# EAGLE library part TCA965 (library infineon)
Window Discriminator Source: http://www.infineon.com/upload/Document/cmc_upload/documents/012/1090/tca965b_green_050217.pdf

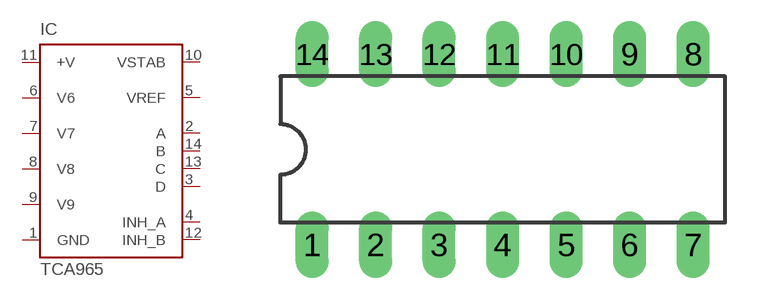
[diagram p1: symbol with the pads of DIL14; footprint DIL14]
Designator prefix IC

## TCA965 (OC_FARNELL: unknown; OC_NEWARK: unknown)  [DIL14]
1  GND  out
2  A  oc
3  D  oc
4  INH_A  in
5  VREF  pas
6  V6  in
7  V7  in
8  V8  in
9  V9  in
10  VSTAB  out
11  +V  out
12  INH_B  in
13  C  oc
14  B  oc

## Footprint DIL14 (pad centres in mm)
Dual In Line Package
drill 0.813 long: 1 -7.62,-3.81; 2 -5.08,-3.81; 3 -2.54,-3.81; 4 0,-3.81; 5 2.54,-3.81; 6 5.08,-3.81; 7 7.62,-3.81; 8 7.62,3.81; 9 5.08,3.81; 10 2.54,3.81; 11 0,3.81; 12 -2.54,3.81; 13 -5.08,3.81; 14 -7.62,3.81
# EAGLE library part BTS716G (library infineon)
Smart High-Side Power Switch Four Channels: 4 x 140mOhm staus Feedback Source: http://www.infineon.com/dgdl/BTS716G.pdf

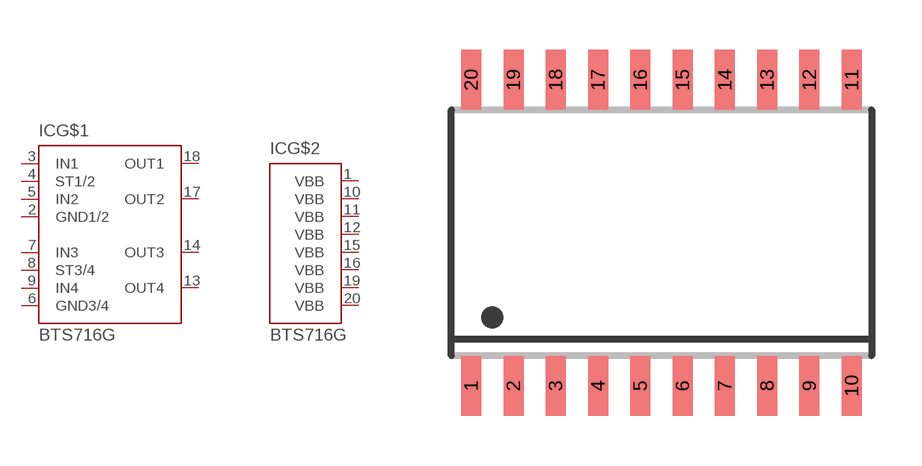
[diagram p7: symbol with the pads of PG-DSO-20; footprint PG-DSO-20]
Designator prefix IC; gates G$1=BTS716G G$2=VBB8

## BTS716G (OC_FARNELL: unknown; OC_NEWARK: unknown)  [PG-DSO-20]
1  G$2:VBB  pwr
2  G$1:GND1/2  in
3  G$1:IN1  in
4  G$1:ST1/2  in
5  G$1:IN2  in
6  G$1:GND3/4  in
7  G$1:IN3  in
8  G$1:ST3/4  in
9  G$1:IN4  in
10  G$2:VBB  pwr
11  G$2:VBB  pwr
12  G$2:VBB  pwr
13  G$1:OUT4  out
14  G$1:OUT3  out
15  G$2:VBB  pwr
16  G$2:VBB  pwr
17  G$1:OUT2  out
18  G$1:OUT1  out
19  G$2:VBB  pwr
20  G$2:VBB  pwr

## Footprint PG-DSO-20 (pad centres in mm)
PG-DSO-20 Plastic Dual Small Outline Package Source: http://www.infineon.com/products .. BTS176G.pdf
smd 0.6 x 1.8: 1 -5.715,-4.6; 2 -4.445,-4.6; 3 -3.175,-4.6; 4 -1.905,-4.6; 5 -0.635,-4.6; 6 0.635,-4.6; 7 1.905,-4.6; 8 3.175,-4.6; 9 4.445,-4.6; 10 5.715,-4.6; 11 5.715,4.6; 12 4.445,4.6; 13 3.175,4.6; 14 1.905,4.6; 15 0.635,4.6; 16 -0.635,4.6; 17 -1.905,4.6; 18 -3.175,4.6; 19 -4.445,4.6; 20 -5.715,4.6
